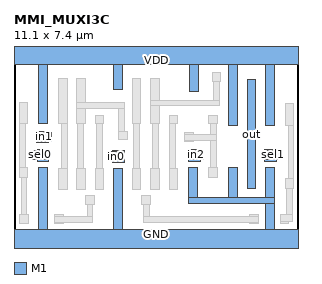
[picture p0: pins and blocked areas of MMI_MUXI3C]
MACRO MMI_MUXI3C
	CLASS CORE ;
	FOREIGN MMI_MUXI3C 0 0 ;
	SIZE 11.1 BY 7.4 ;
	SYMMETRY X Y ;
	SITE CORE1 ;
	PIN out
		DIRECTION output ;
		USE SIGNAL ;
		PORT
			LAYER M1 ;
			RECT 9.075 2.08 9.415 6.315 ;
		END
		AntennaDiffArea 1.485 ;
	END out
	PIN sel0
		DIRECTION input ;
		USE SIGNAL ;
		PORT
			LAYER M1 ;
			RECT 0.905 3.57 1.355 3.59 ;
			LAYER M1 ;
			RECT 0.705 3.23 1.355 3.57 ;
			LAYER M1 ;
			RECT 0.905 3.14 1.355 3.23 ;
		END
		AntennaGateArea 0.7452 ;
	END sel0
	PIN in1
		DIRECTION input ;
		USE SIGNAL ;
		PORT
			LAYER M1 ;
			RECT 0.89 4.265 1.34 4.315 ;
			LAYER M1 ;
			RECT 0.89 3.925 1.46 4.265 ;
			LAYER M1 ;
			RECT 0.89 3.865 1.34 3.925 ;
		END
		AntennaGateArea 0.495 ;
	END in1
	PIN GND
		DIRECTION inout ;
		USE GROUND ;
		PORT
			LAYER M1 ;
			RECT 0.965 0.5 1.305 2.91 ;
			LAYER M1 ;
			RECT 3.885 0.5 4.225 2.88 ;
			LAYER M1 ;
			RECT 6.805 1.725 7.145 2.91 ;
			LAYER M1 ;
			RECT 8.355 1.725 8.695 2.91 ;
			LAYER M1 ;
			RECT 9.795 1.725 10.135 2.91 ;
			LAYER M1 ;
			RECT 6.805 1.495 10.135 1.725 ;
			LAYER M1 ;
			RECT 9.795 0.5 10.135 1.495 ;
			LAYER M1 ;
			RECT 0 -0.5 11.1 0.5 ;
		END
	END GND
	PIN in2
		DIRECTION input ;
		USE SIGNAL ;
		PORT
			LAYER M1 ;
			RECT 6.805 3.57 7.255 3.59 ;
			LAYER M1 ;
			RECT 6.805 3.23 7.37 3.57 ;
			LAYER M1 ;
			RECT 6.805 3.14 7.255 3.23 ;
		END
		AntennaGateArea 0.2484 ;
	END in2
	PIN sel1
		DIRECTION input ;
		USE SIGNAL ;
		PORT
			LAYER M1 ;
			RECT 9.755 3.57 10.205 3.59 ;
			LAYER M1 ;
			RECT 9.755 3.23 10.405 3.57 ;
			LAYER M1 ;
			RECT 9.755 3.14 10.205 3.23 ;
		END
		AntennaGateArea 0.7452 ;
	END sel1
	PIN VDD
		DIRECTION inout ;
		USE POWER ;
		PORT
			LAYER M1 ;
			RECT 0 6.9 11.1 7.9 ;
			LAYER M1 ;
			RECT 0.965 4.6 1.305 6.9 ;
			LAYER M1 ;
			RECT 3.885 5.95 4.225 6.9 ;
			LAYER M1 ;
			RECT 6.845 5.87 7.185 6.9 ;
			LAYER M1 ;
			RECT 8.355 4.555 8.695 6.9 ;
			LAYER M1 ;
			RECT 9.795 4.555 10.135 6.9 ;
		END
	END VDD
	PIN in0
		DIRECTION input ;
		USE SIGNAL ;
		PORT
			LAYER M1 ;
			RECT 3.845 3.51 4.295 3.565 ;
			LAYER M1 ;
			RECT 3.685 3.17 4.295 3.51 ;
			LAYER M1 ;
			RECT 3.845 3.115 4.295 3.17 ;
		END
		AntennaGateArea 0.4968 ;
	END in0
	OBS
		LAYER M1 ;
		RECT 0.205 4.6 0.545 5.44 ;
		LAYER M1 ;
		RECT 1.725 4.6 2.065 6.36 ;
		LAYER M1 ;
		RECT 2.445 5.415 2.785 6.36 ;
		LAYER M1 ;
		RECT 2.445 5.185 4.315 5.415 ;
		LAYER M1 ;
		RECT 2.445 4.6 2.785 5.185 ;
		LAYER M1 ;
		RECT 3.165 4.6 3.505 4.94 ;
		LAYER M1 ;
		RECT 0.21 2.91 0.44 4.6 ;
		LAYER M1 ;
		RECT 0.205 2.53 0.545 2.91 ;
		LAYER M1 ;
		RECT 0.275 1.07 0.505 2.53 ;
		LAYER M1 ;
		RECT 0.225 0.73 0.565 1.07 ;
		LAYER M1 ;
		RECT 1.835 2.88 2.065 4.6 ;
		LAYER M1 ;
		RECT 2.47 2.88 2.7 4.6 ;
		LAYER M1 ;
		RECT 3.22 2.88 3.45 4.6 ;
		LAYER M1 ;
		RECT 4.085 4.32 4.315 5.185 ;
		LAYER M1 ;
		RECT 4.605 4.6 4.945 6.36 ;
		LAYER M1 ;
		RECT 5.325 5.53 5.665 6.36 ;
		LAYER M1 ;
		RECT 7.785 6.605 8.015 6.61 ;
		LAYER M1 ;
		RECT 7.72 6.265 8.06 6.605 ;
		LAYER M1 ;
		RECT 7.785 5.53 8.015 6.265 ;
		LAYER M1 ;
		RECT 5.325 5.3 8.015 5.53 ;
		LAYER M1 ;
		RECT 5.325 4.6 5.665 5.3 ;
		LAYER M1 ;
		RECT 6.045 4.6 6.385 4.94 ;
		LAYER M1 ;
		RECT 7.575 4.6 7.915 4.94 ;
		LAYER M1 ;
		RECT 4.085 3.98 4.425 4.32 ;
		LAYER M1 ;
		RECT 4.655 2.88 4.885 4.6 ;
		LAYER M1 ;
		RECT 5.41 2.88 5.64 4.6 ;
		LAYER M1 ;
		RECT 6.045 2.88 6.275 4.6 ;
		LAYER M1 ;
		RECT 6.65 4.2 6.99 4.265 ;
		LAYER M1 ;
		RECT 7.66 4.2 7.89 4.6 ;
		LAYER M1 ;
		RECT 6.65 3.97 7.89 4.2 ;
		LAYER M1 ;
		RECT 6.65 3.925 6.99 3.97 ;
		LAYER M1 ;
		RECT 7.66 2.91 7.89 3.97 ;
		LAYER M1 ;
		RECT 1.725 2.04 2.065 2.88 ;
		LAYER M1 ;
		RECT 2.445 2.04 2.785 2.88 ;
		LAYER M1 ;
		RECT 3.165 2.04 3.505 2.88 ;
		LAYER M1 ;
		RECT 2.785 1.465 3.125 1.805 ;
		LAYER M1 ;
		RECT 1.58 1.005 1.92 1.07 ;
		LAYER M1 ;
		RECT 2.845 1.005 3.075 1.465 ;
		LAYER M1 ;
		RECT 1.58 0.775 3.075 1.005 ;
		LAYER M1 ;
		RECT 1.58 0.73 1.92 0.775 ;
		LAYER M1 ;
		RECT 4.605 2.04 4.945 2.88 ;
		LAYER M1 ;
		RECT 5.325 2.04 5.665 2.88 ;
		LAYER M1 ;
		RECT 6.045 2.04 6.385 2.88 ;
		LAYER M1 ;
		RECT 4.985 1.465 5.325 1.805 ;
		LAYER M1 ;
		RECT 7.575 2.53 7.915 2.91 ;
		LAYER M1 ;
		RECT 10.565 4.555 10.905 5.395 ;
		LAYER M1 ;
		RECT 10.675 2.46 10.905 4.555 ;
		LAYER M1 ;
		RECT 10.565 2.08 10.905 2.46 ;
		LAYER M1 ;
		RECT 5.035 1.005 5.265 1.465 ;
		LAYER M1 ;
		RECT 9.18 1.005 9.52 1.07 ;
		LAYER M1 ;
		RECT 5.035 0.775 9.52 1.005 ;
		LAYER M1 ;
		RECT 9.18 0.73 9.52 0.775 ;
		LAYER M1 ;
		RECT 10.605 1.07 10.835 2.08 ;
		LAYER M1 ;
		RECT 10.365 0.79 10.835 1.07 ;
		LAYER M1 ;
		RECT 10.365 0.73 10.705 0.79 ;
	END
END MMI_MUXI3C
